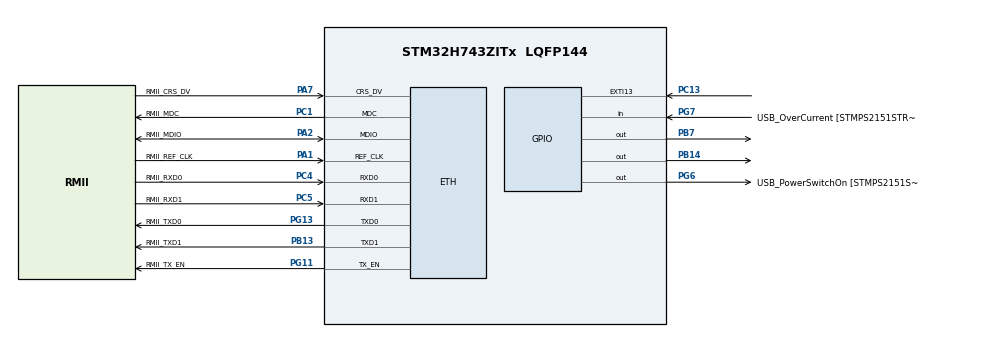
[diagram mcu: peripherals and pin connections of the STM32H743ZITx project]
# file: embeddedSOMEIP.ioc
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CORTEX_M7.default_mode_Activation=1
ETH.MediaInterface=HAL_ETH_RMII_MODE
FREERTOS.Tasks01=defaultTask,24,128,StartDefaultTask,Default,NULL,Dynamic,NULL,NULL
FREERTOS.configUSE_NEWLIB_REENTRANT=1
LWIP.BSP.number=1
LWIP.LWIP_DNS=1
LWIP.LWIP_ICMP=1
LWIP.LWIP_IGMP=1
LWIP.LWIP_MULTICAST_TX_OPTIONS=1
LWIP.MEMP_NUM_UDP_PCB=8
LWIP.Version=v2.2.1_Cube
LWIP0.BSP.STBoard=false
LWIP0.BSP.api=BSP_COMPONENT_DRIVER
LWIP0.BSP.component=LAN8742
LWIP0.BSP.instance=LAN8742
LWIP0.BSP.name=Driver_PHY
LWIP0.BSP.semaphore=S_LAN8742
LWIP0.BSP.solution=LAN8742
Mcu.Family=STM32H7
Mcu.Name=STM32H743ZITx
Mcu.Package=LQFP144
NUCLEO-H743ZI.BUTTON=1
NUCLEO-H743ZI.Bsp_Common_DEMO=true
NUCLEO-H743ZI.LD1=true
NUCLEO-H743ZI.LD2=true
NUCLEO-H743ZI.LD3=true
NUCLEO-H743ZI.VCP=true
NVIC.EXTI15_10_IRQn=true\:5\:0\:false\:false\:true\:true\:false\:true\:true
NVIC.PriorityGroup=NVIC_PRIORITYGROUP_4
NVIC.TIM6_DAC_IRQn=true\:15\:0\:false\:false\:true\:false\:false\:true\:true
NVIC.TimeBase=TIM6_DAC_IRQn
NVIC.TimeBaseIP=TIM6
PA1.GPIO_Label=RMII_REF_CLK
PA1.Mode=RMII
PA1.Signal=ETH_REF_CLK
PA10.GPIO_Label=USB_ID
PA10.Signal=USB_OTG_FS_ID
PA11.GPIO_Label=USB_DM
PA11.Signal=USB_OTG_FS_DM
PA12.GPIO_Label=USB_DP
PA12.Signal=USB_OTG_FS_DP
PA13\ (JTMS/SWDIO).GPIO_Label=TMS
PA13\ (JTMS/SWDIO).Signal=DEBUG_JTMS-SWDIO
PA14\ (JTCK/SWCLK).GPIO_Label=TCK
PA14\ (JTCK/SWCLK).Signal=DEBUG_JTCK-SWCLK
PA2.GPIO_Label=RMII_MDIO
PA2.Mode=RMII
PA2.Signal=ETH_MDIO
PA7.GPIO_Label=RMII_CRS_DV
PA7.Mode=RMII
PA7.Signal=ETH_CRS_DV
PA8.GPIO_Label=USB_SOF [TP1]
PA8.Signal=USB_OTG_FS_SOF
PA9.GPIO_Label=USB_VBUS
PA9.Signal=USB_OTG_FS_VBUS
PB13.GPIO_Label=RMII_TXD1
PB13.Mode=RMII
PB13.Signal=ETH_TXD1
PB14.Signal=GPIO_Output
PB3\ (JTDO/TRACESWO).GPIO_Label=SWO
PB3\ (JTDO/TRACESWO).Signal=DEBUG_JTDO-SWO
PB7.Signal=GPIO_Output
PC1.GPIO_Label=RMII_MDC
PC1.Mode=RMII
PC1.Signal=ETH_MDC
PC13.Signal=GPXTI13
PC14-OSC32_IN\ (OSC32_IN).Signal=RCC_OSC32_IN
PC15-OSC32_OUT\ (OSC32_OUT).Signal=RCC_OSC32_OUT
PC4.GPIO_Label=RMII_RXD0
PC4.Mode=RMII
PC4.Signal=ETH_RXD0
PC5.GPIO_Label=RMII_RXD1
PC5.Mode=RMII
PC5.Signal=ETH_RXD1
PD8.Signal=USART3_TX
PD9.Signal=USART3_RX
PG11.GPIO_Label=RMII_TX_EN
PG11.Mode=RMII
PG11.Signal=ETH_TX_EN
PG13.GPIO_Label=RMII_TXD0
PG13.Mode=RMII
PG13.Signal=ETH_TXD0
PG6.GPIO_Label=USB_PowerSwitchOn [STMPS2151STR_EN]
PG6.Signal=GPIO_Output
PG7.GPIO_Label=USB_OverCurrent [STMPS2151STR_FAULT]
PG7.Signal=GPIO_Input
PH0-OSC_IN\ (PH0).GPIO_Label=MCO
PH0-OSC_IN\ (PH0).Signal=RCC_OSC_IN
ProjectManager.HeapSize=0x200
ProjectManager.StackSize=0x400
ProjectManager.TargetToolchain=STM32CubeIDE
RCC.48MHZClocksFreq_Value=24000000
RCC.ADCFreq_Value=129000000
RCC.AHBFreq_Value=216000000
RCC.APB1CLKDivider=RCC_HCLK_DIV4
RCC.APB1Freq_Value=80000000
RCC.APB1TimFreq_Value=108000000
RCC.APB2CLKDivider=RCC_HCLK_DIV2
RCC.APB2Freq_Value=80000000
RCC.APB2TimFreq_Value=216000000
RCC.APB3Freq_Value=80000000
RCC.APB4Freq_Value=80000000
RCC.CortexFreq_Value=80000000
RCC.DIVM1=4
RCC.DIVN1=10
RCC.DIVQ1=4
RCC.HCLKFreq_Value=80000000
RCC.HSE_VALUE=8000000
RCC.HSI_VALUE=64000000
RCC.PLLM=25
RCC.PLLMUL=RCC_PLL_MUL9
RCC.PLLN=432
RCC.PLLQ=9
RCC.PRESCALERUSB=RCC_USBCLKSOURCE_PLL_DIV1_5
RCC.SYSCLKFreq_VALUE=80000000
RCC.SYSCLKSource=RCC_SYSCLKSOURCE_PLLCLK
RCC.SYSCLKSourceVirtual=RCC_SYSCLKSOURCE_PLLCLK
RCC.USBFreq_Value=40000000
RCC.VCOOutputFreq_Value=432000000
VP_FREERTOS_VS_CMSIS_V2.Mode=CMSIS_V2
VP_LWIP_VS_Enabled.Mode=Enabled
VP_MEMORYMAP_VS_MEMORYMAP.Mode=CurAppReg
VP_NUCLEO-H743ZI_VS_BSP_COMMON.Mode=COMMON
VP_SYS_VS_tim6.Mode=TIM6
board=NUCLEO-H743ZI

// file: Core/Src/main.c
/* USER CODE BEGIN Header */
/**
  ******************************************************************************
  * @file           : main.c
  * @brief          : Main program body
  ******************************************************************************
  * @attention
  *
  * Copyright (c) 2026 STMicroelectronics.
  * All rights reserved.
  *
  * This software is licensed under terms that can be found in the LICENSE file
  * in the root directory of this software component.
  * If no LICENSE file comes with this software, it is provided AS-IS.
  *
  ******************************************************************************
  */
/* USER CODE END Header */
#include "main.h"
#include "FreeRTOS.h"
#include "cmsis_os2.h"
#include "lwip.h"
#include "someip_app.h"   /* C-callable entry point; the C++ SOME/IP code lives in someip_app.cpp */
#include "udp_baseline_app.h" /* plain-UDP echo baseline image, selected with UDP_BASELINE=1 */

COM_InitTypeDef BspCOMInit;
__IO uint32_t BspButtonState = BUTTON_RELEASED;

/* Definitions for defaultTask */
osThreadId_t defaultTaskHandle;
const osThreadAttr_t defaultTask_attributes = {
  .name = "defaultTask",
  .stack_size = 1024 * 4,
  .priority = (osPriority_t) osPriorityNormal,
};

void SystemClock_Config(void);
static void MPU_Config(void);
static void MX_GPIO_Init(void);
void StartDefaultTask(void *argument);

int main(void)
{

  /* MPU Configuration--------------------------------------------------------*/
  MPU_Config();

  /* MCU Configuration--------------------------------------------------------*/

  /* Reset of all peripherals, Initializes the Flash interface and the Systick. */
  HAL_Init();

  /* USER CODE BEGIN Init */

  // I-cache only. D-cache stays off so the CPU and ETH DMA stay coherent without MPU carve-outs.
  // ethernetif.c has a guard that restores cache maintenance if it is ever enabled.
  SCB_EnableICache();

  /* USER CODE END Init */

  /* Configure the system clock */
  SystemClock_Config();

  /* USER CODE BEGIN SysInit */

  // D2 SRAM clocks are off after reset. The FreeRTOS heap lives there.
  // Without this the first heap access bus-faults.
  __HAL_RCC_D2SRAM1_CLK_ENABLE();
  __HAL_RCC_D2SRAM2_CLK_ENABLE();
  __HAL_RCC_D2SRAM3_CLK_ENABLE();

  /* USER CODE END SysInit */

  /* Initialize all configured peripherals */
  MX_GPIO_Init();

  /* Init scheduler */
  osKernelInitialize();

  /* Create the thread(s) */
  /* creation of defaultTask */
  defaultTaskHandle = osThreadNew(StartDefaultTask, NULL, &defaultTask_attributes);

  /* Initialize leds */
  BSP_LED_Init(LED_GREEN);
  BSP_LED_Init(LED_BLUE);
  BSP_LED_Init(LED_RED);

  /* Initialize USER push-button, will be used to trigger an interrupt each time it's pressed.*/
//  BSP_PB_Init(BUTTON_USER, BUTTON_MODE_EXTI);

  /* Initialize COM1 port (115200, 8 bits (7-bit data + 1 stop bit), no parity */
//  BspCOMInit.BaudRate   = 115200;
//  BspCOMInit.WordLength = COM_WORDLENGTH_8B;
//  BspCOMInit.StopBits   = COM_STOPBITS_1;
//  BspCOMInit.Parity     = COM_PARITY_NONE;
//  BspCOMInit.HwFlowCtl  = COM_HWCONTROL_NONE;
//  if (BSP_COM_Init(COM1, &BspCOMInit) != BSP_ERROR_NONE)
//  {
//    Error_Handler();
//  }

  /* USER CODE BEGIN BSP */

  /* -- Sample board code to send message over COM1 port ---- */
  printf("Welcome to STM32 world !\n\r");

  /* -- Sample board code to switch on leds ---- */
  BSP_LED_On(LED_GREEN);
  BSP_LED_On(LED_BLUE);
  BSP_LED_On(LED_RED);

  /* USER CODE END BSP */

  /* Start scheduler */
  osKernelStart();

  /* We should never get here as control is now taken by the scheduler */

  /* Infinite loop */
  /* USER CODE BEGIN WHILE */

  /* USER CODE END 3 */
}

void SystemClock_Config(void)
{
  RCC_OscInitTypeDef RCC_OscInitStruct = {0};
  RCC_ClkInitTypeDef RCC_ClkInitStruct = {0};

  /** Supply configuration update enable
  */
  HAL_PWREx_ConfigSupply(PWR_LDO_SUPPLY);

  /** Configure the main internal regulator output voltage
  *
  * 400 MHz operation needs voltage scale 1 (scale 3 caps the part at 200 MHz
  * and the previous PLL setup only produced 80 MHz SYSCLK, which was the main
  * contributor to the multi-ms network turnaround). NOTE: this function is
  * CubeMX-generated; mirror the 400 MHz clock tree in the .ioc (VOS1, PLL1
  * 16 MHz x50 /2, HCLK 200 MHz, APBx 100 MHz) or a regeneration reverts it.
  */
  __HAL_PWR_VOLTAGESCALING_CONFIG(PWR_REGULATOR_VOLTAGE_SCALE1);

  while(!__HAL_PWR_GET_FLAG(PWR_FLAG_VOSRDY)) {}

  /** Initializes the RCC Oscillators according to the specified parameters
  * in the RCC_OscInitTypeDef structure.
  */
  RCC_OscInitStruct.OscillatorType = RCC_OSCILLATORTYPE_HSI;
  RCC_OscInitStruct.HSIState = RCC_HSI_DIV1;
  RCC_OscInitStruct.HSICalibrationValue = RCC_HSICALIBRATION_DEFAULT;
  RCC_OscInitStruct.PLL.PLLState = RCC_PLL_ON;
  RCC_OscInitStruct.PLL.PLLSource = RCC_PLLSOURCE_HSI;
  RCC_OscInitStruct.PLL.PLLM = 4;   /* 64 MHz HSI / 4 = 16 MHz PLL input   */
  RCC_OscInitStruct.PLL.PLLN = 50;  /* VCO = 16 MHz x 50 = 800 MHz         */
  RCC_OscInitStruct.PLL.PLLP = 2;   /* SYSCLK = 800 / 2 = 400 MHz          */
  RCC_OscInitStruct.PLL.PLLQ = 4;   /* 200 MHz                             */
  RCC_OscInitStruct.PLL.PLLR = 2;
  RCC_OscInitStruct.PLL.PLLRGE = RCC_PLL1VCIRANGE_3;
  RCC_OscInitStruct.PLL.PLLVCOSEL = RCC_PLL1VCOWIDE; /* 800 MHz VCO needs the wide range */
  RCC_OscInitStruct.PLL.PLLFRACN = 0;
  if (HAL_RCC_OscConfig(&RCC_OscInitStruct) != HAL_OK)
  {
    Error_Handler();
  }

  /** Initializes the CPU, AHB and APB buses clocks */
  // CPU 400 MHz, HCLK 200 MHz, APB 100 MHz are the H743 bus limits at VOS1
  // FLASH_LATENCY_2 is required for a 200 MHz AXI clock at VOS1, see RM0433
  RCC_ClkInitStruct.ClockType = RCC_CLOCKTYPE_HCLK|RCC_CLOCKTYPE_SYSCLK
                              |RCC_CLOCKTYPE_PCLK1|RCC_CLOCKTYPE_PCLK2
                              |RCC_CLOCKTYPE_D3PCLK1|RCC_CLOCKTYPE_D1PCLK1;
  RCC_ClkInitStruct.SYSCLKSource = RCC_SYSCLKSOURCE_PLLCLK;
  RCC_ClkInitStruct.SYSCLKDivider = RCC_SYSCLK_DIV1;
  RCC_ClkInitStruct.AHBCLKDivider = RCC_HCLK_DIV2;
  RCC_ClkInitStruct.APB3CLKDivider = RCC_APB3_DIV2;
  RCC_ClkInitStruct.APB1CLKDivider = RCC_APB1_DIV2;
  RCC_ClkInitStruct.APB2CLKDivider = RCC_APB2_DIV2;
  RCC_ClkInitStruct.APB4CLKDivider = RCC_APB4_DIV2;

  if (HAL_RCC_ClockConfig(&RCC_ClkInitStruct, FLASH_LATENCY_2) != HAL_OK)
  {
    Error_Handler();
  }
}

static void MX_GPIO_Init(void)
{
  GPIO_InitTypeDef GPIO_InitStruct = {0};

  /* GPIO Ports Clock Enable */
  __HAL_RCC_GPIOC_CLK_ENABLE();
  __HAL_RCC_GPIOH_CLK_ENABLE();
  __HAL_RCC_GPIOA_CLK_ENABLE();
  __HAL_RCC_GPIOB_CLK_ENABLE();
  __HAL_RCC_GPIOG_CLK_ENABLE();

  /*Configure GPIO pin Output Level */
  HAL_GPIO_WritePin(USB_PowerSwitchOn_GPIO_Port, USB_PowerSwitchOn_Pin, GPIO_PIN_RESET);

  /*Configure GPIO pin : USB_PowerSwitchOn_Pin */
  GPIO_InitStruct.Pin = USB_PowerSwitchOn_Pin;
  GPIO_InitStruct.Mode = GPIO_MODE_OUTPUT_PP;
  GPIO_InitStruct.Pull = GPIO_NOPULL;
  GPIO_InitStruct.Speed = GPIO_SPEED_FREQ_LOW;
  HAL_GPIO_Init(USB_PowerSwitchOn_GPIO_Port, &GPIO_InitStruct);

  /*Configure GPIO pin : USB_OverCurrent_Pin */
  GPIO_InitStruct.Pin = USB_OverCurrent_Pin;
  GPIO_InitStruct.Mode = GPIO_MODE_INPUT;
  GPIO_InitStruct.Pull = GPIO_NOPULL;
  HAL_GPIO_Init(USB_OverCurrent_GPIO_Port, &GPIO_InitStruct);

  /*Configure GPIO pins : USB_SOF_Pin USB_ID_Pin USB_DM_Pin USB_DP_Pin */
  GPIO_InitStruct.Pin = USB_SOF_Pin|USB_ID_Pin|USB_DM_Pin|USB_DP_Pin;
  GPIO_InitStruct.Mode = GPIO_MODE_AF_PP;
  GPIO_InitStruct.Pull = GPIO_NOPULL;
  GPIO_InitStruct.Speed = GPIO_SPEED_FREQ_LOW;
  GPIO_InitStruct.Alternate = GPIO_AF10_OTG1_FS;
  HAL_GPIO_Init(GPIOA, &GPIO_InitStruct);

}

void StartDefaultTask(void *argument)
{

  /* USER CODE BEGIN 5 */

	/* init code for LWIP */
	MX_LWIP_Init();
// Start one application image. Both wait internally for DHCP.
#if defined(UDP_BASELINE) && (UDP_BASELINE)
	udp_baseline_start();
#else
	someip_app_start();
#endif

  /* Infinite loop */
  for(;;)
  {

	 /* -- Sample board code for User push-button in interrupt mode ---- */
	 if (BspButtonState == BUTTON_PRESSED)
	 {
	   /* Update button state */
	   BspButtonState = BUTTON_RELEASED;
	   /* -- Sample board code to toggle leds ---- */
	   BSP_LED_Toggle(LED_GREEN);
	   BSP_LED_Toggle(LED_BLUE);
	   BSP_LED_Toggle(LED_RED);

	   /* ..... Perform your action ..... */
	 }
	 osDelay(20);
  }
  /* USER CODE END 5 */
}

 /* MPU Configuration */

void MPU_Config(void)
{
  MPU_Region_InitTypeDef MPU_InitStruct = {0};

  /* Disables the MPU */
  HAL_MPU_Disable();

  /** Initializes and configures the Region and the memory to be protected
  */
  MPU_InitStruct.Enable = MPU_REGION_ENABLE;
  MPU_InitStruct.Number = MPU_REGION_NUMBER0;
  MPU_InitStruct.BaseAddress = 0x0;
  MPU_InitStruct.Size = MPU_REGION_SIZE_4GB;
  MPU_InitStruct.SubRegionDisable = 0x87;
  MPU_InitStruct.TypeExtField = MPU_TEX_LEVEL0;
  MPU_InitStruct.AccessPermission = MPU_REGION_NO_ACCESS;
  MPU_InitStruct.DisableExec = MPU_INSTRUCTION_ACCESS_DISABLE;
  MPU_InitStruct.IsShareable = MPU_ACCESS_SHAREABLE;
  MPU_InitStruct.IsCacheable = MPU_ACCESS_NOT_CACHEABLE;
  MPU_InitStruct.IsBufferable = MPU_ACCESS_NOT_BUFFERABLE;

  HAL_MPU_ConfigRegion(&MPU_InitStruct);
  /* Enables the MPU */
  HAL_MPU_Enable(MPU_PRIVILEGED_DEFAULT);

}

void HAL_TIM_PeriodElapsedCallback(TIM_HandleTypeDef *htim)
{
  if (htim->Instance == TIM6)
  {
    HAL_IncTick();
  }
}

/**
  * @brief BSP Push Button callback
  * @param Button Specifies the pressed button
  * @retval None
  */
void BSP_PB_Callback(Button_TypeDef Button)
{
  if (Button == BUTTON_USER)
  {
    BspButtonState = BUTTON_PRESSED;
  }
}

void Error_Handler(void)
{
  __disable_irq();
  while (1)
  {
  }
}

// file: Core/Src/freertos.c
/* USER CODE BEGIN Header */
/**
  ******************************************************************************
  * File Name          : freertos.c
  * Description        : Code for freertos applications
  ******************************************************************************
  * @attention
  *
  * Copyright (c) 2026 STMicroelectronics.
  * All rights reserved.
  *
  * This software is licensed under terms that can be found in the LICENSE file
  * in the root directory of this software component.
  * If no LICENSE file comes with this software, it is provided AS-IS.
  *
  ******************************************************************************
  */
/* USER CODE END Header */

#include "FreeRTOS.h"
#include "task.h"
#include "main.h"

/* USER CODE BEGIN Variables */
// Heap sits in D2 SRAM to keep it out of the near-full RAM_D1.
// Needs configAPPLICATION_ALLOCATED_HEAP and the D2 clocks enabled in main.c.
__attribute__((section(".ram_d2"))) uint8_t ucHeap[configTOTAL_HEAP_SIZE];
/* USER CODE END Variables */

/* USER CODE BEGIN Application */

void vApplicationStackOverflowHook(TaskHandle_t xTask, char *pcTaskName)
{
  volatile TaskHandle_t task = xTask;
  volatile char *name = pcTaskName;
  (void)task;
  (void)name;
  taskDISABLE_INTERRUPTS();
  for (;;)
  {
    /* Inspect `name` here to see which task overflowed. */
  }
}

void vApplicationMallocFailedHook(void)
{
  volatile size_t freeHeap = xPortGetFreeHeapSize();
  (void)freeHeap;
  taskDISABLE_INTERRUPTS();
  for (;;)
  {
    // heap exhausted, raise configTOTAL_HEAP_SIZE
  }
}

/* USER CODE END Application */
